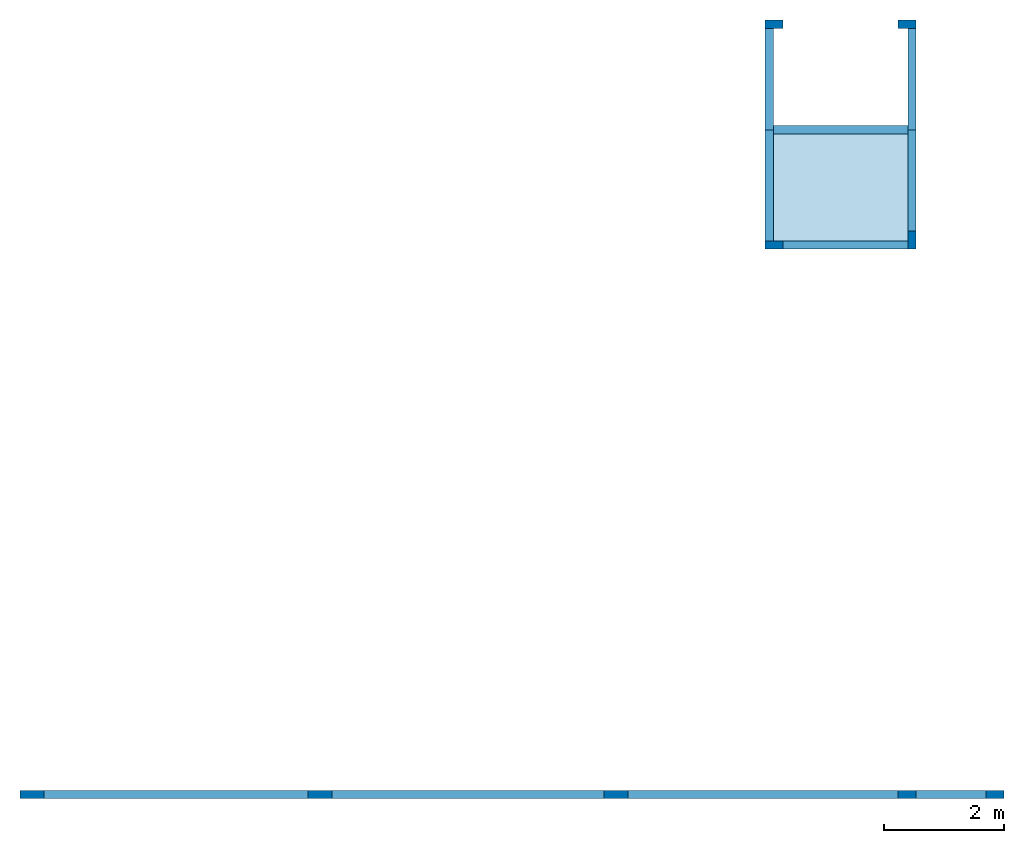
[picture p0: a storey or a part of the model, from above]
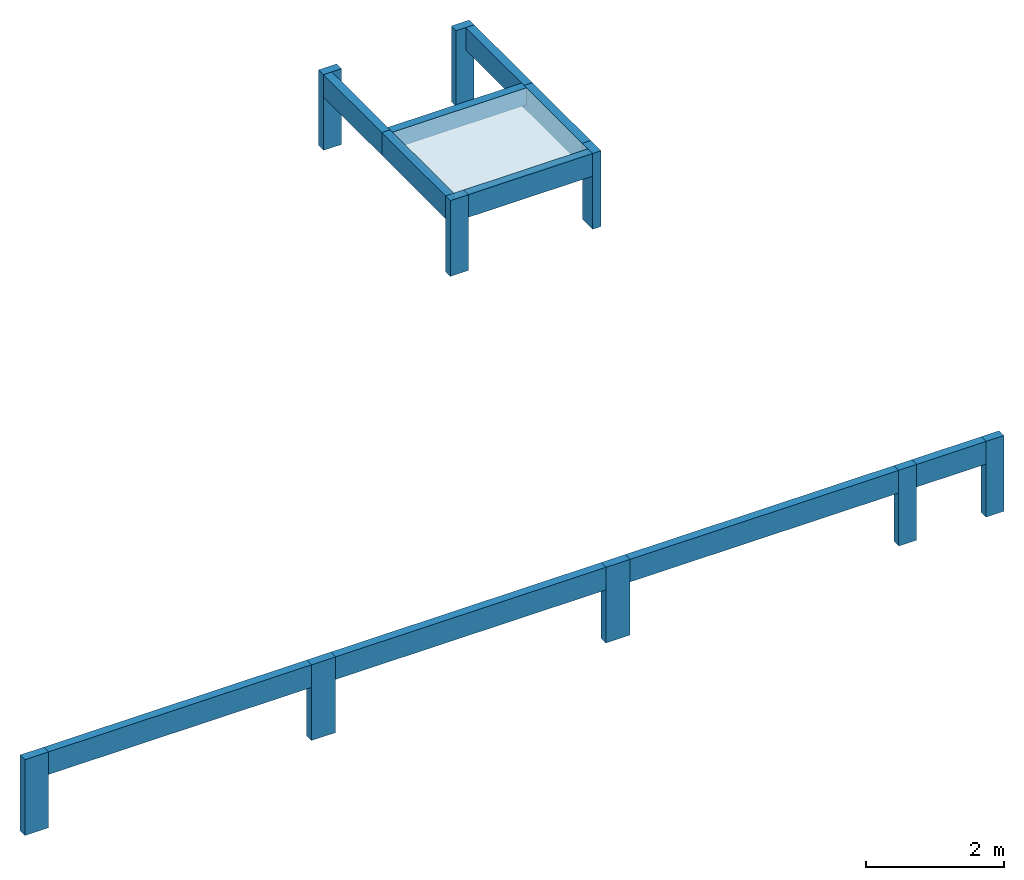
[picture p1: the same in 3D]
Properties of the parts of a building model (IFC4)

# File
Description: IFC4
Time: 2025-07-30T14:34:38
Made in: IfcPlusPlus

# IfcBuildingStorey (4)
Name | LongName | Elevation (cm)
BALDRAME-FUNDAÇÃO | BALDRAME-FUNDAÇÃO | 24
RESPALDO | RESPALDO | 336
PLATIBANDA | PLATIBANDA | 470
TORRE CX DE ÁGUA | TORRE CX DE ÁGUA | 620

# IfcBeam (125)
Material: Concreto
Pset_ConcreteElementGeneral - ConcreteCover: 3 cm; ConstructionMethod: InSitu; ExposureClass: 2; StrengthClass: C-25
AltoQi_Eberick_Elemento - Elemento: Viga; Tipo: retangular
AltoQi_Eberick_Padrão - Ambiente: Externo; Cobrimento: 3 cm; Classe de concreto: C-25
AltoQi_Eberick_Cargas - Adicional (G2): 0; Solo (S): 0; Acidental (Q): 0; Água (A): 0; Subpressão (AS): 0
Pset_BeamCommon - IsExternal: yes; LoadBearing: yes
Name | In | Seção_bw (cm) | Seção_h (cm) | Elevação (cm) | Taxa de armadura | Cargas de parede (G2) | Reference
4 x V1 | BALDRAME-FUNDAÇÃO | 14 | 30 | 0 | 0.24 % | 546 | Viga C-25 - Seção Retangular 14 X 30
2 x V10 | BALDRAME-FUNDAÇÃO | 14 | 30 | 0 | 0.36 % | 546 | Viga C-25 - Seção Retangular 14 X 30
7 x V11 | BALDRAME-FUNDAÇÃO | 14 | 30 | 0 | 0.24 % | 546 | Viga C-25 - Seção Retangular 14 X 30
V12 | BALDRAME-FUNDAÇÃO | 16 | 30 | 0 | 0.21 % | 546 | Viga C-25 - Seção Retangular 16 X 30
2 x V13 | BALDRAME-FUNDAÇÃO | 14 | 30 | 0 | 0.24 % | 0 | Viga C-25 - Seção Retangular 14 X 30
2 x V14 | BALDRAME-FUNDAÇÃO | 14 | 30 | 0 | 0.24 % | 0 | Viga C-25 - Seção Retangular 14 X 30
2 x V15 | BALDRAME-FUNDAÇÃO | 14 | 30 | 0 | 0.24 % | 0 | Viga C-25 - Seção Retangular 14 X 30
V16 | BALDRAME-FUNDAÇÃO | 14 | 30 | 0 | 0.24 % | 331.5 | Viga C-25 - Seção Retangular 14 X 30
3 x V16 | BALDRAME-FUNDAÇÃO | 14 | 30 | 0 | 0.24 % | 390 | Viga C-25 - Seção Retangular 14 X 30
V2 | BALDRAME-FUNDAÇÃO | 14 | 30 | 0 | 0.24 % | 546 | Viga C-25 - Seção Retangular 14 X 30
6 x V3 | BALDRAME-FUNDAÇÃO | 14 | 30 | 0 | 0.24 % | 546 | Viga C-25 - Seção Retangular 14 X 30
6 x V4 | BALDRAME-FUNDAÇÃO | 14 | 30 | 0 | 0.24 % | 546 | Viga C-25 - Seção Retangular 14 X 30
V4 | BALDRAME-FUNDAÇÃO | 14 | 30 | 0 | 0.24 % | 331.5 | Viga C-25 - Seção Retangular 14 X 30
2 x V5 | BALDRAME-FUNDAÇÃO | 14 | 30 | 0 | 0.24 % | 0 | Viga C-25 - Seção Retangular 14 X 30
2 x V6 | BALDRAME-FUNDAÇÃO | 14 | 30 | 0 | 0.24 % | 282.75 | Viga C-25 - Seção Retangular 14 X 30
5 x V7 | BALDRAME-FUNDAÇÃO | 14 | 30 | 0 | 0.24 % | 546 | Viga C-25 - Seção Retangular 14 X 30
V8 | BALDRAME-FUNDAÇÃO | 14 | 30 | 0 | 0.24 % | 546 | Viga C-25 - Seção Retangular 14 X 30
V9 | BALDRAME-FUNDAÇÃO | 14 | 30 | 0 | 0.24 % | 546 | Viga C-25 - Seção Retangular 14 X 30
4 x V1 | RESPALDO | 14 | 40 | 0 | 0.18 % | 0 | Viga C-25 - Seção Retangular 14 X 40
V10 | RESPALDO | 14 | 30 | 0 | 0.24 % | 0 | Viga C-25 - Seção Retangular 14 X 30
V11 | RESPALDO | 20 | 35 | 0 | 0.34 % | 0 | Viga C-25 - Seção Retangular 20 X 35
V11 | RESPALDO | 20 | 35 | 0 | 0.14 % | 0 | Viga C-25 - Seção Retangular 20 X 35
V11 | RESPALDO | 20 | 35 | 0 | 0.22 % | 0 | Viga C-25 - Seção Retangular 20 X 35
V12 | RESPALDO | 14 | 30 | 0 | 0.24 % | 0 | Viga C-25 - Seção Retangular 14 X 30
V13 | RESPALDO | 14 | 30 | 0 | 0.24 % | 0 | Viga C-25 - Seção Retangular 14 X 30
7 x V14 | RESPALDO | 14 | 40 | 0 | 0.18 % | 0 | Viga C-25 - Seção Retangular 14 X 40
V15 | RESPALDO | 15 | 40 | 0 | 0.17 % | 0 | Viga C-25 - Seção Retangular 15 X 40
2 x V16 | RESPALDO | 14 | 40 | 0 | 0.18 % | 0 | Viga C-25 - Seção Retangular 14 X 40
2 x V17 | RESPALDO | 14 | 40 | 0 | 0.18 % | 0 | Viga C-25 - Seção Retangular 14 X 40
2 x V18 | RESPALDO | 14 | 40 | 0 | 0.18 % | 0 | Viga C-25 - Seção Retangular 14 X 40
2 x V19 | RESPALDO | 15 | 40 | 0 | 0.17 % | 0 | Viga C-25 - Seção Retangular 15 X 40
5 x V2 | RESPALDO | 14 | 40 | 0 | 0.18 % | 0 | Viga C-25 - Seção Retangular 14 X 40
2 x V2 | RESPALDO | 14 | 40 | 0 | 0.27 % | 0 | Viga C-25 - Seção Retangular 14 X 40
2 x V20 | RESPALDO | 14 | 30 | 0 | 0.24 % | 0 | Viga C-25 - Seção Retangular 14 X 30
3 x V21 | RESPALDO | 14 | 30 | 35 | 0.24 % | 97.5 | Viga C-25 - Seção Retangular 14 X 30
3 x V3 | RESPALDO | 14 | 30 | 0 | 0.24 % | 0 | Viga C-25 - Seção Retangular 14 X 30
9 x V4 | RESPALDO | 14 | 40 | 0 | 0.18 % | 0 | Viga C-25 - Seção Retangular 14 X 40
2 x V5 | RESPALDO | 14 | 30 | 0 | 0.24 % | 0 | Viga C-25 - Seção Retangular 14 X 30
6 x V6 | RESPALDO | 14 | 40 | 0 | 0.18 % | 0 | Viga C-25 - Seção Retangular 14 X 40
2 x V7 | RESPALDO | 20 | 35 | 0 | 0.29 % | 0 | Viga C-25 - Seção Retangular 20 X 35
V8 | RESPALDO | 14 | 30 | 0 | 0.24 % | 0 | Viga C-25 - Seção Retangular 14 X 30
V9 | RESPALDO | 14 | 40 | 0 | 0.18 % | 0 | Viga C-25 - Seção Retangular 14 X 40
V1 | PLATIBANDA | 14 | 30 | 0 | 0.24 % | 0 | Viga C-25 - Seção Retangular 14 X 30
V2 | PLATIBANDA | 14 | 40 | 0 | 0.18 % | 0 | Viga C-25 - Seção Retangular 14 X 40
4 x V3 | PLATIBANDA | 14 | 40 | 0 | 0.18 % | 0 | Viga C-25 - Seção Retangular 14 X 40
2 x V4 | PLATIBANDA | 14 | 40 | 0 | 0.18 % | 0 | Viga C-25 - Seção Retangular 14 X 40
2 x V5 | PLATIBANDA | 14 | 40 | 0 | 0.18 % | 0 | Viga C-25 - Seção Retangular 14 X 40
V1 | TORRE CX DE ÁGUA | 14 | 40 | 0 | 0.18 % | 0 | Viga C-25 - Seção Retangular 14 X 40
V2 | TORRE CX DE ÁGUA | 14 | 40 | 0 | 0.18 % | 0 | Viga C-25 - Seção Retangular 14 X 40
V3 | TORRE CX DE ÁGUA | 14 | 40 | 0 | 0.18 % | 0 | Viga C-25 - Seção Retangular 14 X 40
V4 | TORRE CX DE ÁGUA | 14 | 40 | 0 | 0.18 % | 0 | Viga C-25 - Seção Retangular 14 X 40

# IfcColumn (71)
Material: Concreto
Pset_ConcreteElementGeneral - ConcreteCover: 3 cm; ConstructionMethod: InSitu; ExposureClass: 2; StrengthClass: C-25
AltoQi_Eberick_Elemento - Elemento: Pilar; Tipo: retangular
AltoQi_Eberick_Padrão - Ambiente: Externo; Cobrimento: 3 cm; Classe de concreto: C-25
Pset_ColumnCommon - IsExternal: yes; LoadBearing: yes
Name | In | Seção_b (cm) | Seção_h (cm) | Elevação (cm) | Taxa de armadura | Taxa de compressão bruta | Taxa de compressão homogeneizada | Reference
P1 | BALDRAME-FUNDAÇÃO | 14 | 30 | 0 | 0.75 % | 0.06 | 0.05 | Pilar C-25 - Retangular 14x30
P10 | BALDRAME-FUNDAÇÃO | 14 | 30 | 0 | 0.75 % | 0.08 | 0.07 | Pilar C-25 - Retangular 14x30
P11 | BALDRAME-FUNDAÇÃO | 14 | 30 | 0 | 0.75 % | 0.08 | 0.07 | Pilar C-25 - Retangular 14x30
P12 | BALDRAME-FUNDAÇÃO | 20 | 20 | 0 | 0.79 % | 0.14 | 0.11 | Pilar C-25 - Retangular 20x20
P13 | BALDRAME-FUNDAÇÃO | 20 | 20 | 0 | 0.79 % | 0.13 | 0.11 | Pilar C-25 - Retangular 20x20
P14 | BALDRAME-FUNDAÇÃO | 14 | 30 | 0 | 0.75 % | 0.08 | 0.07 | Pilar C-25 - Retangular 14x30
P15 | BALDRAME-FUNDAÇÃO | 14 | 30 | 0 | 0.75 % | 0.08 | 0.07 | Pilar C-25 - Retangular 14x30
P16 | BALDRAME-FUNDAÇÃO | 14 | 30 | 0 | 0.75 % | 0.01 | 0.01 | Pilar C-25 - Retangular 14x30
P17 | BALDRAME-FUNDAÇÃO | 14 | 40 | 0 | 0.84 % | 0.08 | 0.07 | Pilar C-25 - Retangular 14x40
P18 | BALDRAME-FUNDAÇÃO | 14 | 40 | 0 | 0.84 % | 0.11 | 0.09 | Pilar C-25 - Retangular 14x40
P19 | BALDRAME-FUNDAÇÃO | 14 | 40 | 0 | 0.84 % | 0.13 | 0.11 | Pilar C-25 - Retangular 14x40
P2 | BALDRAME-FUNDAÇÃO | 14 | 30 | 0 | 1.12 % | 0.1 | 0.08 | Pilar C-25 - Retangular 14x30
P20 | BALDRAME-FUNDAÇÃO | 14 | 30 | 0 | 0.75 % | 0.12 | 0.1 | Pilar C-25 - Retangular 14x30
P21 | BALDRAME-FUNDAÇÃO | 14 | 30 | 0 | 0.75 % | 0.03 | 0.02 | Pilar C-25 - Retangular 14x30
P22 | BALDRAME-FUNDAÇÃO | 14 | 40 | 0 | 0.84 % | 0.02 | 0.02 | Pilar C-25 - Retangular 14x40
P23 | BALDRAME-FUNDAÇÃO | 14 | 40 | 0 | 0.84 % | 0.03 | 0.02 | Pilar C-25 - Retangular 14x40
P24 | BALDRAME-FUNDAÇÃO | 14 | 40 | 0 | 0.84 % | 0.03 | 0.02 | Pilar C-25 - Retangular 14x40
P25 | BALDRAME-FUNDAÇÃO | 15 | 40 | 0 | 0.79 % | 0.02 | 0.02 | Pilar C-25 - Retangular 15x40
P26 | BALDRAME-FUNDAÇÃO | 14 | 40 | 0 | 0.84 % | 0.01 | 0.01 | Pilar C-25 - Retangular 14x40
P27 | BALDRAME-FUNDAÇÃO | 14 | 40 | 0 | 0.84 % | 0.01 | 0.01 | Pilar C-25 - Retangular 14x40
P28 | BALDRAME-FUNDAÇÃO | 14 | 40 | 0 | 0.84 % | 0.02 | 0.01 | Pilar C-25 - Retangular 14x40
P29 | BALDRAME-FUNDAÇÃO | 14 | 40 | 0 | 0.84 % | 0.01 | 0.01 | Pilar C-25 - Retangular 14x40
P3 | BALDRAME-FUNDAÇÃO | 14 | 30 | 0 | 2.34 % | 0.13 | 0.09 | Pilar C-25 - Retangular 14x30
P4 | BALDRAME-FUNDAÇÃO | 14 | 30 | 0 | 1.75 % | 0.09 | 0.06 | Pilar C-25 - Retangular 14x30
P5 | BALDRAME-FUNDAÇÃO | 14 | 30 | 0 | 0.75 % | 0.08 | 0.07 | Pilar C-25 - Retangular 14x30
P6 | BALDRAME-FUNDAÇÃO | 14 | 40 | 0 | 0.84 % | 0.09 | 0.08 | Pilar C-25 - Retangular 14x40
P7 | BALDRAME-FUNDAÇÃO | 14 | 30 | 0 | 0.75 % | 0.15 | 0.13 | Pilar C-25 - Retangular 14x30
P8 | BALDRAME-FUNDAÇÃO | 14 | 30 | 0 | 1.75 % | 0.16 | 0.12 | Pilar C-25 - Retangular 14x30
P9 | BALDRAME-FUNDAÇÃO | 14 | 30 | 0 | 1.17 % | 0.13 | 0.1 | Pilar C-25 - Retangular 14x30
P1 | RESPALDO | 14 | 30 | 0 | 0.75 % | 0.02 | 0.02 | Pilar C-25 - Retangular 14x30
P10 | RESPALDO | 14 | 30 | 0 | 0.75 % | 0.05 | 0.04 | Pilar C-25 - Retangular 14x30
P11 | RESPALDO | 14 | 30 | 0 | 0.75 % | 0.04 | 0.04 | Pilar C-25 - Retangular 14x30
P12 | RESPALDO | 20 | 20 | 0 | 0.79 % | 0.14 | 0.11 | Pilar C-25 - Retangular 20x20
P13 | RESPALDO | 20 | 20 | 0 | 0.79 % | 0.13 | 0.11 | Pilar C-25 - Retangular 20x20
P14 | RESPALDO | 14 | 30 | 0 | 0.75 % | 0.04 | 0.04 | Pilar C-25 - Retangular 14x30
P15 | RESPALDO | 14 | 30 | 0 | 0.75 % | 0.05 | 0.04 | Pilar C-25 - Retangular 14x30
P16 | RESPALDO | 14 | 30 | 35 | 0.75 % | 0.01 | 0.01 | Pilar C-25 - Retangular 14x30
P17 | RESPALDO | 14 | 40 | 0 | 0.84 % | 0.03 | 0.03 | Pilar C-25 - Retangular 14x40
P18 | RESPALDO | 14 | 40 | 0 | 0.84 % | 0.07 | 0.06 | Pilar C-25 - Retangular 14x40
P19 | RESPALDO | 14 | 40 | 0 | 0.84 % | 0.09 | 0.08 | Pilar C-25 - Retangular 14x40
P2 | RESPALDO | 14 | 30 | 0 | 0.75 % | 0.04 | 0.03 | Pilar C-25 - Retangular 14x30
P20 | RESPALDO | 14 | 30 | 0 | 0.75 % | 0.05 | 0.05 | Pilar C-25 - Retangular 14x30
P21 | RESPALDO | 14 | 30 | 0 | 0.75 % | 0.02 | 0.01 | Pilar C-25 - Retangular 14x30
P22 | RESPALDO | 14 | 40 | 0 | 0.84 % | 0.02 | 0.02 | Pilar C-25 - Retangular 14x40
P23 | RESPALDO | 14 | 40 | 0 | 0.84 % | 0.02 | 0.02 | Pilar C-25 - Retangular 14x40
P24 | RESPALDO | 14 | 40 | 0 | 0.84 % | 0.02 | 0.02 | Pilar C-25 - Retangular 14x40
P25 | RESPALDO | 15 | 40 | 0 | 0.79 % | 0.01 | 0.01 | Pilar C-25 - Retangular 15x40
P26 | RESPALDO | 14 | 40 | 35 | 0.84 % | 0.01 | 0.01 | Pilar C-25 - Retangular 14x40
P27 | RESPALDO | 14 | 40 | 0 | 0.84 % | 0 | 0 | Pilar C-25 - Retangular 14x40
P28 | RESPALDO | 14 | 40 | 0 | 0.84 % | 0.01 | 0.01 | Pilar C-25 - Retangular 14x40
P29 | RESPALDO | 14 | 40 | 0 | 0.84 % | 0 | 0 | Pilar C-25 - Retangular 14x40
P3 | RESPALDO | 14 | 30 | 0 | 2.34 % | 0.06 | 0.04 | Pilar C-25 - Retangular 14x30
P4 | RESPALDO | 14 | 30 | 0 | 1.75 % | 0.04 | 0.03 | Pilar C-25 - Retangular 14x30
P5 | RESPALDO | 14 | 30 | 0 | 0.75 % | 0.03 | 0.03 | Pilar C-25 - Retangular 14x30
P6 | RESPALDO | 14 | 40 | 0 | 0.84 % | 0.04 | 0.04 | Pilar C-25 - Retangular 14x40
P7 | RESPALDO | 14 | 30 | 0 | 0.75 % | 0.07 | 0.06 | Pilar C-25 - Retangular 14x30
P8 | RESPALDO | 14 | 30 | 0 | 1.75 % | 0.09 | 0.06 | Pilar C-25 - Retangular 14x30
P9 | RESPALDO | 14 | 30 | 0 | 1.17 % | 0.07 | 0.05 | Pilar C-25 - Retangular 14x30
P17 | PLATIBANDA | 14 | 40 | 0 | 0.84 % | 0.01 | 0.01 | Pilar C-25 - Retangular 14x40
P18 | PLATIBANDA | 14 | 40 | 0 | 0.84 % | 0.01 | 0.01 | Pilar C-25 - Retangular 14x40
P19 | PLATIBANDA | 14 | 40 | 0 | 0.84 % | 0.01 | 0.01 | Pilar C-25 - Retangular 14x40
P20 | PLATIBANDA | 14 | 30 | 0 | 0.75 % | 0.01 | 0.01 | Pilar C-25 - Retangular 14x30
P21 | PLATIBANDA | 14 | 30 | 0 | 0.75 % | 0 | 0 | Pilar C-25 - Retangular 14x30
P3 | PLATIBANDA | 14 | 30 | 0 | 2.34 % | 0.02 | 0.02 | Pilar C-25 - Retangular 14x30
P4 | PLATIBANDA | 14 | 30 | 0 | 1.75 % | 0.02 | 0.02 | Pilar C-25 - Retangular 14x30
P8 | PLATIBANDA | 14 | 30 | 0 | 1.75 % | 0.03 | 0.02 | Pilar C-25 - Retangular 14x30
P9 | PLATIBANDA | 14 | 30 | 0 | 1.17 % | 0.03 | 0.02 | Pilar C-25 - Retangular 14x30
P3 | TORRE CX DE ÁGUA | 14 | 30 | 0 | 2.34 % | 0.01 | 0.01 | Pilar C-25 - Retangular 14x30
P4 | TORRE CX DE ÁGUA | 14 | 30 | 0 | 1.75 % | 0.01 | 0.01 | Pilar C-25 - Retangular 14x30
P8 | TORRE CX DE ÁGUA | 14 | 30 | 0 | 1.75 % | 0.01 | 0.01 | Pilar C-25 - Retangular 14x30
P9 | TORRE CX DE ÁGUA | 14 | 30 | 0 | 1.17 % | 0.01 | 0.01 | Pilar C-25 - Retangular 14x30

# IfcFooting (29)
In: BALDRAME-FUNDAÇÃO
Material: Concreto
Pset_ConcreteElementGeneral - ConcreteCover: 4.5 cm; ConstructionMethod: InSitu; ExposureClass: 2; StrengthClass: C-25
AltoQi_Eberick_Elemento - Elemento: Bloco; Seção_LH: 50 cm; Elevação: 0 cm
AltoQi_Eberick_Padrão - Cobrimento: 4.5 cm; Classe de concreto: C-25
Pset_PileCommon - Reference: Estaca circular R30 - Concreto C-25
Pset_FootingCommon - Reference: Bloco C-25
Name | Tipo | Seção_LB (cm)
P1 | 1 | 50
P10 | 1 | 50
P11 | 1 | 50
P12 | 2 | 110
P13 | 2 | 110
P14 | 1 | 50
P15 | 1 | 50
P16 | 1 | 50
P17 | 1 | 50
P18 | 1 | 50
P19 | 1 | 50
P2 | 1 | 50
P20 | 1 | 50
P21 | 1 | 50
P22 | 1 | 50
P23 | 1 | 50
P24 | 1 | 50
P25 | 1 | 50
P26 | 1 | 50
P27 | 1 | 50
P28 | 1 | 50
P29 | 1 | 50
P3 | 1 | 50
P4 | 1 | 50
P5 | 1 | 50
P6 | 1 | 50
P7 | 1 | 50
P8 | 1 | 50
P9 | 1 | 50

# IfcPile (31)
In: BALDRAME-FUNDAÇÃO
Material: Concreto
Pset_ConcreteElementGeneral - ConcreteCover: 4.5 cm; ConstructionMethod: InSitu; ExposureClass: 2; StrengthClass: C-25
AltoQi_Eberick_Elemento - Elemento: Bloco; Seção_LH: 50 cm; Elevação: 0 cm
AltoQi_Eberick_Padrão - Cobrimento: 4.5 cm; Classe de concreto: C-25
Pset_PileCommon - Reference: Estaca circular R30 - Concreto C-25
Pset_FootingCommon - Reference: Bloco C-25
Name | Tipo | Seção_LB (cm)
E1-1 | 1 | 50
E10-1 | 1 | 50
E11-1 | 1 | 50
E12-1 | 2 | 110
E12-2 | 2 | 110
E13-1 | 2 | 110
E13-2 | 2 | 110
E14-1 | 1 | 50
E15-1 | 1 | 50
E16-1 | 1 | 50
E17-1 | 1 | 50
E18-1 | 1 | 50
E19-1 | 1 | 50
E2-1 | 1 | 50
E20-1 | 1 | 50
E21-1 | 1 | 50
E22-1 | 1 | 50
E23-1 | 1 | 50
E24-1 | 1 | 50
E25-1 | 1 | 50
E26-1 | 1 | 50
E27-1 | 1 | 50
E28-1 | 1 | 50
E29-1 | 1 | 50
E3-1 | 1 | 50
E4-1 | 1 | 50
E5-1 | 1 | 50
E6-1 | 1 | 50
E7-1 | 1 | 50
E8-1 | 1 | 50
E9-1 | 1 | 50

# IfcSlab (13)
PredefinedType: FLOOR; Material: Concreto
Pset_ConcreteElementGeneral - ConcreteCover: 2.5 cm; ConstructionMethod: InSitu; ExposureClass: 2; StrengthClass: C-25
AltoQi_Eberick_Elemento - Elemento: Laje; Elevação: 0 cm
AltoQi_Eberick_Padrão - Ambiente: Externo; Cobrimento: 2.5 cm; Classe de concreto: C-25
AltoQi_Eberick_Cargas - Revestimento (G2): 50; Adicional (G2): 0; Solo (S): 0; Água (A): 0; Subpressão (AS): 0
Pset_SlabCommon - LoadBearing: yes; IsExternal: yes; PitchAngle: 0 rad
Name | In | Tipo | Espessura (cm) | Acidental (Q) | Reference
L1 | RESPALDO | Pré-moldada | 12 | 50 | Laje Pré-moldada - h=12cm
L10 | RESPALDO | Maciça | 8 | 50 | Laje Maciça - h=8cm
L11 | RESPALDO | Maciça | 8 | 50 | Laje Maciça - h=8cm
L12 | RESPALDO | Maciça | 8 | 50 | Laje Maciça - h=8cm
L2 | RESPALDO | Pré-moldada | 12 | 50 | Laje Pré-moldada - h=12cm
L3 | RESPALDO | Pré-moldada | 12 | 50 | Laje Pré-moldada - h=12cm
L4 | RESPALDO | Pré-moldada | 12 | 50 | Laje Pré-moldada - h=12cm
L5 | RESPALDO | Pré-moldada | 12 | 50 | Laje Pré-moldada - h=12cm
L6 | RESPALDO | Pré-moldada | 12 | 50 | Laje Pré-moldada - h=12cm
L7 | RESPALDO | Pré-moldada | 12 | 50 | Laje Pré-moldada - h=12cm
L8 | RESPALDO | Pré-moldada | 12 | 50 | Laje Pré-moldada - h=12cm
L9 | RESPALDO | Pré-moldada | 12 | 50 | Laje Pré-moldada - h=12cm
L1 | PLATIBANDA | Maciça | 10 | 1000 | Laje Maciça - h=10cm
